# Copyright lowRISC contributors (OpenTitan project).
# Licensed under the Apache License, Version 2.0, see LICENSE for details.
# SPDX-License-Identifier: Apache-2.0
#
# This file was derived by lowRISC contributors (OpenTitan project) from the
# IHP Open PDK SRAM abstract RM_IHPSG13_1P_8192x32_c4.lef
# (https://github.com/IHP-GmbH/IHP-Open-PDK, ihp-sg13g2/libs.ref/sg13g2_sram/lef).
# It is a synthetic abstract, not an IHP release: the macro size and pins come
# from the Liberty view, the pin shapes, power straps and antenna values from
# the IHP abstract. IHP's original notice follows:
#
#   Copyright 2023 IHP PDK Authors
#
#   Licensed under the Apache License, Version 2.0 (the "License");
#   you may not use this file except in compliance with the License.
#   You may obtain a copy of the License at
#
#      https://www.apache.org/licenses/LICENSE-2.0
#
#   Unless required by applicable law or agreed to in writing, software
#   distributed under the License is distributed on an "AS IS" BASIS,
#   WITHOUT WARRANTIES OR CONDITIONS OF ANY KIND, either express or implied.
#   See the License for the specific language governing permissions and
#   limitations under the License.
#
#   Generated on Mon Apr  7 14:15:46 2025
#
# Generated by gen_synthetic_lef.py from the Liberty view. Do not edit.
# Synthetic abstract: no physical layout exists behind this macro.

VERSION 5.7 ;
BUSBITCHARS "[]" ;
DIVIDERCHAR "/" ;

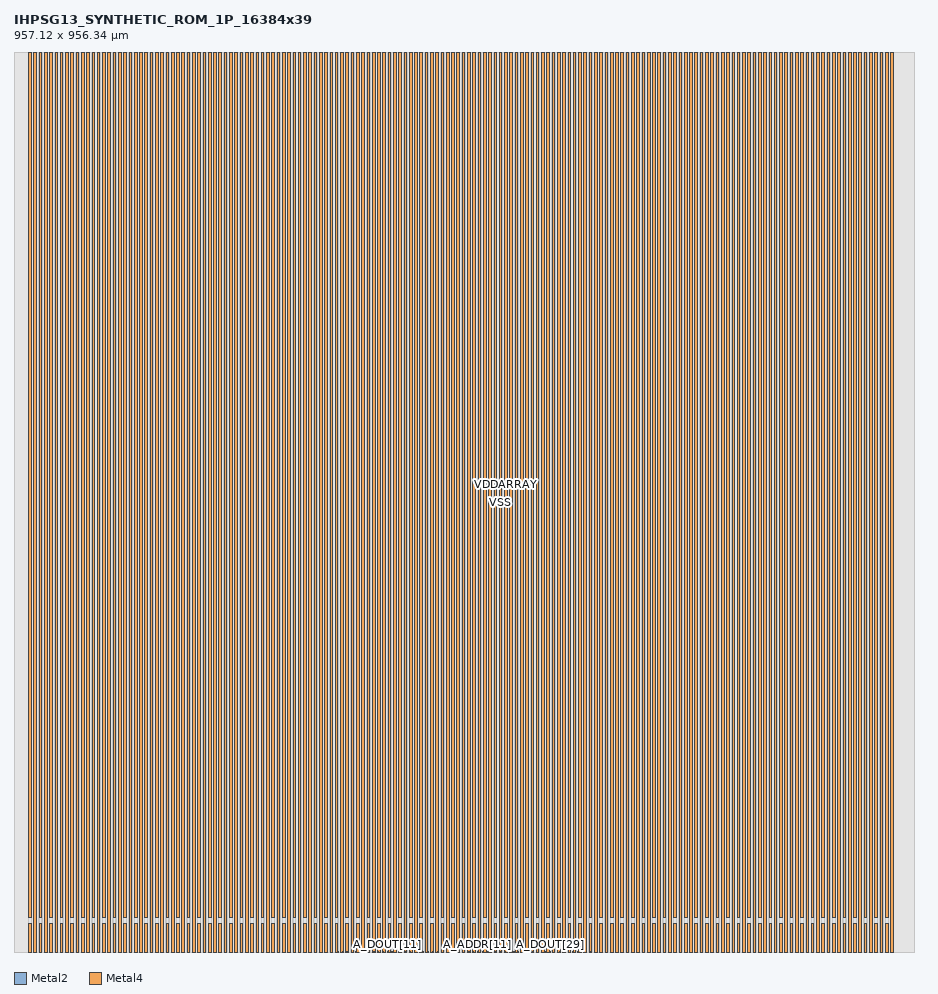
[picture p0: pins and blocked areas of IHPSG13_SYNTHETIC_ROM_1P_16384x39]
MACRO IHPSG13_SYNTHETIC_ROM_1P_16384x39
  CLASS BLOCK ;
  ORIGIN 0 0 ;
  FOREIGN IHPSG13_SYNTHETIC_ROM_1P_16384x39 0 0 ;
  SIZE 957.12 BY 956.34 ;
  SYMMETRY X Y R90 ;
  PIN A_DOUT[0]
    DIRECTION OUTPUT ;
    USE SIGNAL ;
    ANTENNADIFFAREA 0.988 LAYER Metal2 ;
    PORT
      LAYER Metal2 ;
        RECT 344.03 0 344.29 0.26 ;
    END
  END A_DOUT[0]
  PIN A_DOUT[1]
    DIRECTION OUTPUT ;
    USE SIGNAL ;
    ANTENNADIFFAREA 0.988 LAYER Metal2 ;
    PORT
      LAYER Metal2 ;
        RECT 348.83 0 349.09 0.26 ;
    END
  END A_DOUT[1]
  PIN A_DOUT[2]
    DIRECTION OUTPUT ;
    USE SIGNAL ;
    ANTENNADIFFAREA 0.988 LAYER Metal2 ;
    PORT
      LAYER Metal2 ;
        RECT 353.63 0 353.89 0.26 ;
    END
  END A_DOUT[2]
  PIN A_DOUT[3]
    DIRECTION OUTPUT ;
    USE SIGNAL ;
    ANTENNADIFFAREA 0.988 LAYER Metal2 ;
    PORT
      LAYER Metal2 ;
        RECT 358.43 0 358.69 0.26 ;
    END
  END A_DOUT[3]
  PIN A_DOUT[4]
    DIRECTION OUTPUT ;
    USE SIGNAL ;
    ANTENNADIFFAREA 0.988 LAYER Metal2 ;
    PORT
      LAYER Metal2 ;
        RECT 363.23 0 363.49 0.26 ;
    END
  END A_DOUT[4]
  PIN A_DOUT[5]
    DIRECTION OUTPUT ;
    USE SIGNAL ;
    ANTENNADIFFAREA 0.988 LAYER Metal2 ;
    PORT
      LAYER Metal2 ;
        RECT 368.03 0 368.29 0.26 ;
    END
  END A_DOUT[5]
  PIN A_DOUT[6]
    DIRECTION OUTPUT ;
    USE SIGNAL ;
    ANTENNADIFFAREA 0.988 LAYER Metal2 ;
    PORT
      LAYER Metal2 ;
        RECT 372.83 0 373.09 0.26 ;
    END
  END A_DOUT[6]
  PIN A_DOUT[7]
    DIRECTION OUTPUT ;
    USE SIGNAL ;
    ANTENNADIFFAREA 0.988 LAYER Metal2 ;
    PORT
      LAYER Metal2 ;
        RECT 377.63 0 377.89 0.26 ;
    END
  END A_DOUT[7]
  PIN A_DOUT[8]
    DIRECTION OUTPUT ;
    USE SIGNAL ;
    ANTENNADIFFAREA 0.988 LAYER Metal2 ;
    PORT
      LAYER Metal2 ;
        RECT 382.43 0 382.69 0.26 ;
    END
  END A_DOUT[8]
  PIN A_DOUT[9]
    DIRECTION OUTPUT ;
    USE SIGNAL ;
    ANTENNADIFFAREA 0.988 LAYER Metal2 ;
    PORT
      LAYER Metal2 ;
        RECT 387.23 0 387.49 0.26 ;
    END
  END A_DOUT[9]
  PIN A_DOUT[10]
    DIRECTION OUTPUT ;
    USE SIGNAL ;
    ANTENNADIFFAREA 0.988 LAYER Metal2 ;
    PORT
      LAYER Metal2 ;
        RECT 392.03 0 392.29 0.26 ;
    END
  END A_DOUT[10]
  PIN A_DOUT[11]
    DIRECTION OUTPUT ;
    USE SIGNAL ;
    ANTENNADIFFAREA 0.988 LAYER Metal2 ;
    PORT
      LAYER Metal2 ;
        RECT 396.83 0 397.09 0.26 ;
    END
  END A_DOUT[11]
  PIN A_DOUT[12]
    DIRECTION OUTPUT ;
    USE SIGNAL ;
    ANTENNADIFFAREA 0.988 LAYER Metal2 ;
    PORT
      LAYER Metal2 ;
        RECT 401.63 0 401.89 0.26 ;
    END
  END A_DOUT[12]
  PIN A_DOUT[13]
    DIRECTION OUTPUT ;
    USE SIGNAL ;
    ANTENNADIFFAREA 0.988 LAYER Metal2 ;
    PORT
      LAYER Metal2 ;
        RECT 406.43 0 406.69 0.26 ;
    END
  END A_DOUT[13]
  PIN A_DOUT[14]
    DIRECTION OUTPUT ;
    USE SIGNAL ;
    ANTENNADIFFAREA 0.988 LAYER Metal2 ;
    PORT
      LAYER Metal2 ;
        RECT 411.23 0 411.49 0.26 ;
    END
  END A_DOUT[14]
  PIN A_DOUT[15]
    DIRECTION OUTPUT ;
    USE SIGNAL ;
    ANTENNADIFFAREA 0.988 LAYER Metal2 ;
    PORT
      LAYER Metal2 ;
        RECT 416.03 0 416.29 0.26 ;
    END
  END A_DOUT[15]
  PIN A_DOUT[16]
    DIRECTION OUTPUT ;
    USE SIGNAL ;
    ANTENNADIFFAREA 0.988 LAYER Metal2 ;
    PORT
      LAYER Metal2 ;
        RECT 420.83 0 421.09 0.26 ;
    END
  END A_DOUT[16]
  PIN A_DOUT[17]
    DIRECTION OUTPUT ;
    USE SIGNAL ;
    ANTENNADIFFAREA 0.988 LAYER Metal2 ;
    PORT
      LAYER Metal2 ;
        RECT 425.63 0 425.89 0.26 ;
    END
  END A_DOUT[17]
  PIN A_DOUT[18]
    DIRECTION OUTPUT ;
    USE SIGNAL ;
    ANTENNADIFFAREA 0.988 LAYER Metal2 ;
    PORT
      LAYER Metal2 ;
        RECT 430.43 0 430.69 0.26 ;
    END
  END A_DOUT[18]
  PIN A_DLY
    DIRECTION INPUT ;
    USE SIGNAL ;
    ANTENNAMODEL OXIDE1 ;
      ANTENNAGATEAREA 0.20085 LAYER Metal2 ;
    PORT
      LAYER Metal2 ;
        RECT 435.23 0 435.49 0.26 ;
    END
  END A_DLY
  PIN A_ADDR[0]
    DIRECTION INPUT ;
    USE SIGNAL ;
    ANTENNAMODEL OXIDE1 ;
      ANTENNAGATEAREA 0.20085 LAYER Metal2 ;
    PORT
      LAYER Metal2 ;
        RECT 440.03 0 440.29 0.26 ;
    END
  END A_ADDR[0]
  PIN A_ADDR[1]
    DIRECTION INPUT ;
    USE SIGNAL ;
    ANTENNAMODEL OXIDE1 ;
      ANTENNAGATEAREA 0.20085 LAYER Metal2 ;
    PORT
      LAYER Metal2 ;
        RECT 444.83 0 445.09 0.26 ;
    END
  END A_ADDR[1]
  PIN A_ADDR[2]
    DIRECTION INPUT ;
    USE SIGNAL ;
    ANTENNAMODEL OXIDE1 ;
      ANTENNAGATEAREA 0.20085 LAYER Metal2 ;
    PORT
      LAYER Metal2 ;
        RECT 449.63 0 449.89 0.26 ;
    END
  END A_ADDR[2]
  PIN A_ADDR[3]
    DIRECTION INPUT ;
    USE SIGNAL ;
    ANTENNAMODEL OXIDE1 ;
      ANTENNAGATEAREA 0.20085 LAYER Metal2 ;
    PORT
      LAYER Metal2 ;
        RECT 454.43 0 454.69 0.26 ;
    END
  END A_ADDR[3]
  PIN A_ADDR[4]
    DIRECTION INPUT ;
    USE SIGNAL ;
    ANTENNAMODEL OXIDE1 ;
      ANTENNAGATEAREA 0.20085 LAYER Metal2 ;
    PORT
      LAYER Metal2 ;
        RECT 459.23 0 459.49 0.26 ;
    END
  END A_ADDR[4]
  PIN A_ADDR[5]
    DIRECTION INPUT ;
    USE SIGNAL ;
    ANTENNAMODEL OXIDE1 ;
      ANTENNAGATEAREA 0.20085 LAYER Metal2 ;
    PORT
      LAYER Metal2 ;
        RECT 464.03 0 464.29 0.26 ;
    END
  END A_ADDR[5]
  PIN A_ADDR[6]
    DIRECTION INPUT ;
    USE SIGNAL ;
    ANTENNAMODEL OXIDE1 ;
      ANTENNAGATEAREA 0.20085 LAYER Metal2 ;
    PORT
      LAYER Metal2 ;
        RECT 468.83 0 469.09 0.26 ;
    END
  END A_ADDR[6]
  PIN A_ADDR[7]
    DIRECTION INPUT ;
    USE SIGNAL ;
    ANTENNAMODEL OXIDE1 ;
      ANTENNAGATEAREA 0.20085 LAYER Metal2 ;
    PORT
      LAYER Metal2 ;
        RECT 473.63 0 473.89 0.26 ;
    END
  END A_ADDR[7]
  PIN A_ADDR[8]
    DIRECTION INPUT ;
    USE SIGNAL ;
    ANTENNAMODEL OXIDE1 ;
      ANTENNAGATEAREA 0.20085 LAYER Metal2 ;
    PORT
      LAYER Metal2 ;
        RECT 478.43 0 478.69 0.26 ;
    END
  END A_ADDR[8]
  PIN A_ADDR[9]
    DIRECTION INPUT ;
    USE SIGNAL ;
    ANTENNAMODEL OXIDE1 ;
      ANTENNAGATEAREA 0.20085 LAYER Metal2 ;
    PORT
      LAYER Metal2 ;
        RECT 483.23 0 483.49 0.26 ;
    END
  END A_ADDR[9]
  PIN A_ADDR[10]
    DIRECTION INPUT ;
    USE SIGNAL ;
    ANTENNAMODEL OXIDE1 ;
      ANTENNAGATEAREA 0.20085 LAYER Metal2 ;
    PORT
      LAYER Metal2 ;
        RECT 488.03 0 488.29 0.26 ;
    END
  END A_ADDR[10]
  PIN A_ADDR[11]
    DIRECTION INPUT ;
    USE SIGNAL ;
    ANTENNAMODEL OXIDE1 ;
      ANTENNAGATEAREA 0.20085 LAYER Metal2 ;
    PORT
      LAYER Metal2 ;
        RECT 492.83 0 493.09 0.26 ;
    END
  END A_ADDR[11]
  PIN A_ADDR[12]
    DIRECTION INPUT ;
    USE SIGNAL ;
    ANTENNAMODEL OXIDE1 ;
      ANTENNAGATEAREA 0.20085 LAYER Metal2 ;
    PORT
      LAYER Metal2 ;
        RECT 497.63 0 497.89 0.26 ;
    END
  END A_ADDR[12]
  PIN A_ADDR[13]
    DIRECTION INPUT ;
    USE SIGNAL ;
    ANTENNAMODEL OXIDE1 ;
      ANTENNAGATEAREA 0.20085 LAYER Metal2 ;
    PORT
      LAYER Metal2 ;
        RECT 502.43 0 502.69 0.26 ;
    END
  END A_ADDR[13]
  PIN A_REN
    DIRECTION INPUT ;
    USE SIGNAL ;
    ANTENNAMODEL OXIDE1 ;
      ANTENNAGATEAREA 0.20085 LAYER Metal2 ;
    PORT
      LAYER Metal2 ;
        RECT 507.23 0 507.49 0.26 ;
    END
  END A_REN
  PIN A_MEN
    DIRECTION INPUT ;
    USE SIGNAL ;
    ANTENNAMODEL OXIDE1 ;
      ANTENNAGATEAREA 0.20085 LAYER Metal2 ;
    PORT
      LAYER Metal2 ;
        RECT 512.03 0 512.29 0.26 ;
    END
  END A_MEN
  PIN A_CLK
    DIRECTION INPUT ;
    USE SIGNAL ;
    ANTENNAMODEL OXIDE1 ;
      ANTENNAGATEAREA 0.20085 LAYER Metal2 ;
    PORT
      LAYER Metal2 ;
        RECT 516.83 0 517.09 0.26 ;
    END
  END A_CLK
  PIN A_DOUT[19]
    DIRECTION OUTPUT ;
    USE SIGNAL ;
    ANTENNADIFFAREA 0.988 LAYER Metal2 ;
    PORT
      LAYER Metal2 ;
        RECT 521.63 0 521.89 0.26 ;
    END
  END A_DOUT[19]
  PIN A_DOUT[20]
    DIRECTION OUTPUT ;
    USE SIGNAL ;
    ANTENNADIFFAREA 0.988 LAYER Metal2 ;
    PORT
      LAYER Metal2 ;
        RECT 526.43 0 526.69 0.26 ;
    END
  END A_DOUT[20]
  PIN A_DOUT[21]
    DIRECTION OUTPUT ;
    USE SIGNAL ;
    ANTENNADIFFAREA 0.988 LAYER Metal2 ;
    PORT
      LAYER Metal2 ;
        RECT 531.23 0 531.49 0.26 ;
    END
  END A_DOUT[21]
  PIN A_DOUT[22]
    DIRECTION OUTPUT ;
    USE SIGNAL ;
    ANTENNADIFFAREA 0.988 LAYER Metal2 ;
    PORT
      LAYER Metal2 ;
        RECT 536.03 0 536.29 0.26 ;
    END
  END A_DOUT[22]
  PIN A_DOUT[23]
    DIRECTION OUTPUT ;
    USE SIGNAL ;
    ANTENNADIFFAREA 0.988 LAYER Metal2 ;
    PORT
      LAYER Metal2 ;
        RECT 540.83 0 541.09 0.26 ;
    END
  END A_DOUT[23]
  PIN A_DOUT[24]
    DIRECTION OUTPUT ;
    USE SIGNAL ;
    ANTENNADIFFAREA 0.988 LAYER Metal2 ;
    PORT
      LAYER Metal2 ;
        RECT 545.63 0 545.89 0.26 ;
    END
  END A_DOUT[24]
  PIN A_DOUT[25]
    DIRECTION OUTPUT ;
    USE SIGNAL ;
    ANTENNADIFFAREA 0.988 LAYER Metal2 ;
    PORT
      LAYER Metal2 ;
        RECT 550.43 0 550.69 0.26 ;
    END
  END A_DOUT[25]
  PIN A_DOUT[26]
    DIRECTION OUTPUT ;
    USE SIGNAL ;
    ANTENNADIFFAREA 0.988 LAYER Metal2 ;
    PORT
      LAYER Metal2 ;
        RECT 555.23 0 555.49 0.26 ;
    END
  END A_DOUT[26]
  PIN A_DOUT[27]
    DIRECTION OUTPUT ;
    USE SIGNAL ;
    ANTENNADIFFAREA 0.988 LAYER Metal2 ;
    PORT
      LAYER Metal2 ;
        RECT 560.03 0 560.29 0.26 ;
    END
  END A_DOUT[27]
  PIN A_DOUT[28]
    DIRECTION OUTPUT ;
    USE SIGNAL ;
    ANTENNADIFFAREA 0.988 LAYER Metal2 ;
    PORT
      LAYER Metal2 ;
        RECT 564.83 0 565.09 0.26 ;
    END
  END A_DOUT[28]
  PIN A_DOUT[29]
    DIRECTION OUTPUT ;
    USE SIGNAL ;
    ANTENNADIFFAREA 0.988 LAYER Metal2 ;
    PORT
      LAYER Metal2 ;
        RECT 569.63 0 569.89 0.26 ;
    END
  END A_DOUT[29]
  PIN A_DOUT[30]
    DIRECTION OUTPUT ;
    USE SIGNAL ;
    ANTENNADIFFAREA 0.988 LAYER Metal2 ;
    PORT
      LAYER Metal2 ;
        RECT 574.43 0 574.69 0.26 ;
    END
  END A_DOUT[30]
  PIN A_DOUT[31]
    DIRECTION OUTPUT ;
    USE SIGNAL ;
    ANTENNADIFFAREA 0.988 LAYER Metal2 ;
    PORT
      LAYER Metal2 ;
        RECT 579.23 0 579.49 0.26 ;
    END
  END A_DOUT[31]
  PIN A_DOUT[32]
    DIRECTION OUTPUT ;
    USE SIGNAL ;
    ANTENNADIFFAREA 0.988 LAYER Metal2 ;
    PORT
      LAYER Metal2 ;
        RECT 584.03 0 584.29 0.26 ;
    END
  END A_DOUT[32]
  PIN A_DOUT[33]
    DIRECTION OUTPUT ;
    USE SIGNAL ;
    ANTENNADIFFAREA 0.988 LAYER Metal2 ;
    PORT
      LAYER Metal2 ;
        RECT 588.83 0 589.09 0.26 ;
    END
  END A_DOUT[33]
  PIN A_DOUT[34]
    DIRECTION OUTPUT ;
    USE SIGNAL ;
    ANTENNADIFFAREA 0.988 LAYER Metal2 ;
    PORT
      LAYER Metal2 ;
        RECT 593.63 0 593.89 0.26 ;
    END
  END A_DOUT[34]
  PIN A_DOUT[35]
    DIRECTION OUTPUT ;
    USE SIGNAL ;
    ANTENNADIFFAREA 0.988 LAYER Metal2 ;
    PORT
      LAYER Metal2 ;
        RECT 598.43 0 598.69 0.26 ;
    END
  END A_DOUT[35]
  PIN A_DOUT[36]
    DIRECTION OUTPUT ;
    USE SIGNAL ;
    ANTENNADIFFAREA 0.988 LAYER Metal2 ;
    PORT
      LAYER Metal2 ;
        RECT 603.23 0 603.49 0.26 ;
    END
  END A_DOUT[36]
  PIN A_DOUT[37]
    DIRECTION OUTPUT ;
    USE SIGNAL ;
    ANTENNADIFFAREA 0.988 LAYER Metal2 ;
    PORT
      LAYER Metal2 ;
        RECT 608.03 0 608.29 0.26 ;
    END
  END A_DOUT[37]
  PIN A_DOUT[38]
    DIRECTION OUTPUT ;
    USE SIGNAL ;
    ANTENNADIFFAREA 0.988 LAYER Metal2 ;
    PORT
      LAYER Metal2 ;
        RECT 612.83 0 613.09 0.26 ;
    END
  END A_DOUT[38]
  PIN VDD
    DIRECTION INOUT ;
    USE POWER ;
    PORT
      LAYER Metal4 ;
        RECT 15.5 0 18.31 30.425 ;
    END
    PORT
      LAYER Metal4 ;
        RECT 26.74 0 29.55 30.425 ;
    END
    PORT
      LAYER Metal4 ;
        RECT 37.98 0 40.79 30.425 ;
    END
    PORT
      LAYER Metal4 ;
        RECT 49.22 0 52.03 30.425 ;
    END
    PORT
      LAYER Metal4 ;
        RECT 60.46 0 63.27 30.425 ;
    END
    PORT
      LAYER Metal4 ;
        RECT 71.7 0 74.51 30.425 ;
    END
    PORT
      LAYER Metal4 ;
        RECT 82.94 0 85.75 30.425 ;
    END
    PORT
      LAYER Metal4 ;
        RECT 94.18 0 96.99 30.425 ;
    END
    PORT
      LAYER Metal4 ;
        RECT 105.42 0 108.23 30.425 ;
    END
    PORT
      LAYER Metal4 ;
        RECT 116.66 0 119.47 30.425 ;
    END
    PORT
      LAYER Metal4 ;
        RECT 127.9 0 130.71 30.425 ;
    END
    PORT
      LAYER Metal4 ;
        RECT 139.14 0 141.95 30.425 ;
    END
    PORT
      LAYER Metal4 ;
        RECT 150.38 0 153.19 30.425 ;
    END
    PORT
      LAYER Metal4 ;
        RECT 161.62 0 164.43 30.425 ;
    END
    PORT
      LAYER Metal4 ;
        RECT 172.86 0 175.67 30.425 ;
    END
    PORT
      LAYER Metal4 ;
        RECT 184.1 0 186.91 30.425 ;
    END
    PORT
      LAYER Metal4 ;
        RECT 195.34 0 198.15 30.425 ;
    END
    PORT
      LAYER Metal4 ;
        RECT 206.58 0 209.39 30.425 ;
    END
    PORT
      LAYER Metal4 ;
        RECT 217.82 0 220.63 30.425 ;
    END
    PORT
      LAYER Metal4 ;
        RECT 229.06 0 231.87 30.425 ;
    END
    PORT
      LAYER Metal4 ;
        RECT 240.3 0 243.11 30.425 ;
    END
    PORT
      LAYER Metal4 ;
        RECT 251.54 0 254.35 30.425 ;
    END
    PORT
      LAYER Metal4 ;
        RECT 262.78 0 265.59 30.425 ;
    END
    PORT
      LAYER Metal4 ;
        RECT 274.02 0 276.83 30.425 ;
    END
    PORT
      LAYER Metal4 ;
        RECT 285.26 0 288.07 30.425 ;
    END
    PORT
      LAYER Metal4 ;
        RECT 296.5 0 299.31 30.425 ;
    END
    PORT
      LAYER Metal4 ;
        RECT 307.74 0 310.55 30.425 ;
    END
    PORT
      LAYER Metal4 ;
        RECT 318.98 0 321.79 30.425 ;
    END
    PORT
      LAYER Metal4 ;
        RECT 330.22 0 333.03 30.425 ;
    END
    PORT
      LAYER Metal4 ;
        RECT 341.46 0 344.27 30.425 ;
    END
    PORT
      LAYER Metal4 ;
        RECT 352.7 0 355.51 30.425 ;
    END
    PORT
      LAYER Metal4 ;
        RECT 363.94 0 366.75 30.425 ;
    END
    PORT
      LAYER Metal4 ;
        RECT 375.18 0 377.99 30.425 ;
    END
    PORT
      LAYER Metal4 ;
        RECT 386.42 0 389.23 30.425 ;
    END
    PORT
      LAYER Metal4 ;
        RECT 397.66 0 400.47 30.425 ;
    END
    PORT
      LAYER Metal4 ;
        RECT 408.9 0 411.71 30.425 ;
    END
    PORT
      LAYER Metal4 ;
        RECT 420.14 0 422.95 30.425 ;
    END
    PORT
      LAYER Metal4 ;
        RECT 431.38 0 434.19 30.425 ;
    END
    PORT
      LAYER Metal4 ;
        RECT 442.62 0 445.43 30.425 ;
    END
    PORT
      LAYER Metal4 ;
        RECT 453.86 0 456.67 30.425 ;
    END
    PORT
      LAYER Metal4 ;
        RECT 465.1 0 467.91 30.425 ;
    END
    PORT
      LAYER Metal4 ;
        RECT 476.34 0 479.15 30.425 ;
    END
    PORT
      LAYER Metal4 ;
        RECT 487.58 0 490.39 30.425 ;
    END
    PORT
      LAYER Metal4 ;
        RECT 498.82 0 501.63 30.425 ;
    END
    PORT
      LAYER Metal4 ;
        RECT 510.06 0 512.87 30.425 ;
    END
    PORT
      LAYER Metal4 ;
        RECT 521.3 0 524.11 30.425 ;
    END
    PORT
      LAYER Metal4 ;
        RECT 532.54 0 535.35 30.425 ;
    END
    PORT
      LAYER Metal4 ;
        RECT 543.78 0 546.59 30.425 ;
    END
    PORT
      LAYER Metal4 ;
        RECT 555.02 0 557.83 30.425 ;
    END
    PORT
      LAYER Metal4 ;
        RECT 566.26 0 569.07 30.425 ;
    END
    PORT
      LAYER Metal4 ;
        RECT 577.5 0 580.31 30.425 ;
    END
    PORT
      LAYER Metal4 ;
        RECT 588.74 0 591.55 30.425 ;
    END
    PORT
      LAYER Metal4 ;
        RECT 599.98 0 602.79 30.425 ;
    END
    PORT
      LAYER Metal4 ;
        RECT 611.22 0 614.03 30.425 ;
    END
    PORT
      LAYER Metal4 ;
        RECT 622.46 0 625.27 30.425 ;
    END
    PORT
      LAYER Metal4 ;
        RECT 633.7 0 636.51 30.425 ;
    END
    PORT
      LAYER Metal4 ;
        RECT 644.94 0 647.75 30.425 ;
    END
    PORT
      LAYER Metal4 ;
        RECT 656.18 0 658.99 30.425 ;
    END
    PORT
      LAYER Metal4 ;
        RECT 667.42 0 670.23 30.425 ;
    END
    PORT
      LAYER Metal4 ;
        RECT 678.66 0 681.47 30.425 ;
    END
    PORT
      LAYER Metal4 ;
        RECT 689.9 0 692.71 30.425 ;
    END
    PORT
      LAYER Metal4 ;
        RECT 701.14 0 703.95 30.425 ;
    END
    PORT
      LAYER Metal4 ;
        RECT 712.38 0 715.19 30.425 ;
    END
    PORT
      LAYER Metal4 ;
        RECT 723.62 0 726.43 30.425 ;
    END
    PORT
      LAYER Metal4 ;
        RECT 734.86 0 737.67 30.425 ;
    END
    PORT
      LAYER Metal4 ;
        RECT 746.1 0 748.91 30.425 ;
    END
    PORT
      LAYER Metal4 ;
        RECT 757.34 0 760.15 30.425 ;
    END
    PORT
      LAYER Metal4 ;
        RECT 768.58 0 771.39 30.425 ;
    END
    PORT
      LAYER Metal4 ;
        RECT 779.82 0 782.63 30.425 ;
    END
    PORT
      LAYER Metal4 ;
        RECT 791.06 0 793.87 30.425 ;
    END
    PORT
      LAYER Metal4 ;
        RECT 802.3 0 805.11 30.425 ;
    END
    PORT
      LAYER Metal4 ;
        RECT 813.54 0 816.35 30.425 ;
    END
    PORT
      LAYER Metal4 ;
        RECT 824.78 0 827.59 30.425 ;
    END
    PORT
      LAYER Metal4 ;
        RECT 836.02 0 838.83 30.425 ;
    END
    PORT
      LAYER Metal4 ;
        RECT 847.26 0 850.07 30.425 ;
    END
    PORT
      LAYER Metal4 ;
        RECT 858.5 0 861.31 30.425 ;
    END
    PORT
      LAYER Metal4 ;
        RECT 869.74 0 872.55 30.425 ;
    END
    PORT
      LAYER Metal4 ;
        RECT 880.98 0 883.79 30.425 ;
    END
    PORT
      LAYER Metal4 ;
        RECT 892.22 0 895.03 30.425 ;
    END
    PORT
      LAYER Metal4 ;
        RECT 903.46 0 906.27 30.425 ;
    END
    PORT
      LAYER Metal4 ;
        RECT 914.7 0 917.51 30.425 ;
    END
    PORT
      LAYER Metal4 ;
        RECT 925.94 0 928.75 30.425 ;
    END
  END VDD
  PIN VDDARRAY
    DIRECTION INOUT ;
    USE POWER ;
    PORT
      LAYER Metal4 ;
        RECT 15.5 37.065 18.31 956.34 ;
    END
    PORT
      LAYER Metal4 ;
        RECT 26.74 37.065 29.55 956.34 ;
    END
    PORT
      LAYER Metal4 ;
        RECT 37.98 37.065 40.79 956.34 ;
    END
    PORT
      LAYER Metal4 ;
        RECT 49.22 37.065 52.03 956.34 ;
    END
    PORT
      LAYER Metal4 ;
        RECT 60.46 37.065 63.27 956.34 ;
    END
    PORT
      LAYER Metal4 ;
        RECT 71.7 37.065 74.51 956.34 ;
    END
    PORT
      LAYER Metal4 ;
        RECT 82.94 37.065 85.75 956.34 ;
    END
    PORT
      LAYER Metal4 ;
        RECT 94.18 37.065 96.99 956.34 ;
    END
    PORT
      LAYER Metal4 ;
        RECT 105.42 37.065 108.23 956.34 ;
    END
    PORT
      LAYER Metal4 ;
        RECT 116.66 37.065 119.47 956.34 ;
    END
    PORT
      LAYER Metal4 ;
        RECT 127.9 37.065 130.71 956.34 ;
    END
    PORT
      LAYER Metal4 ;
        RECT 139.14 37.065 141.95 956.34 ;
    END
    PORT
      LAYER Metal4 ;
        RECT 150.38 37.065 153.19 956.34 ;
    END
    PORT
      LAYER Metal4 ;
        RECT 161.62 37.065 164.43 956.34 ;
    END
    PORT
      LAYER Metal4 ;
        RECT 172.86 37.065 175.67 956.34 ;
    END
    PORT
      LAYER Metal4 ;
        RECT 184.1 37.065 186.91 956.34 ;
    END
    PORT
      LAYER Metal4 ;
        RECT 195.34 37.065 198.15 956.34 ;
    END
    PORT
      LAYER Metal4 ;
        RECT 206.58 37.065 209.39 956.34 ;
    END
    PORT
      LAYER Metal4 ;
        RECT 217.82 37.065 220.63 956.34 ;
    END
    PORT
      LAYER Metal4 ;
        RECT 229.06 37.065 231.87 956.34 ;
    END
    PORT
      LAYER Metal4 ;
        RECT 240.3 37.065 243.11 956.34 ;
    END
    PORT
      LAYER Metal4 ;
        RECT 251.54 37.065 254.35 956.34 ;
    END
    PORT
      LAYER Metal4 ;
        RECT 262.78 37.065 265.59 956.34 ;
    END
    PORT
      LAYER Metal4 ;
        RECT 274.02 37.065 276.83 956.34 ;
    END
    PORT
      LAYER Metal4 ;
        RECT 285.26 37.065 288.07 956.34 ;
    END
    PORT
      LAYER Metal4 ;
        RECT 296.5 37.065 299.31 956.34 ;
    END
    PORT
      LAYER Metal4 ;
        RECT 307.74 37.065 310.55 956.34 ;
    END
    PORT
      LAYER Metal4 ;
        RECT 318.98 37.065 321.79 956.34 ;
    END
    PORT
      LAYER Metal4 ;
        RECT 330.22 37.065 333.03 956.34 ;
    END
    PORT
      LAYER Metal4 ;
        RECT 341.46 37.065 344.27 956.34 ;
    END
    PORT
      LAYER Metal4 ;
        RECT 352.7 37.065 355.51 956.34 ;
    END
    PORT
      LAYER Metal4 ;
        RECT 363.94 37.065 366.75 956.34 ;
    END
    PORT
      LAYER Metal4 ;
        RECT 375.18 37.065 377.99 956.34 ;
    END
    PORT
      LAYER Metal4 ;
        RECT 386.42 37.065 389.23 956.34 ;
    END
    PORT
      LAYER Metal4 ;
        RECT 397.66 37.065 400.47 956.34 ;
    END
    PORT
      LAYER Metal4 ;
        RECT 408.9 37.065 411.71 956.34 ;
    END
    PORT
      LAYER Metal4 ;
        RECT 420.14 37.065 422.95 956.34 ;
    END
    PORT
      LAYER Metal4 ;
        RECT 431.38 37.065 434.19 956.34 ;
    END
    PORT
      LAYER Metal4 ;
        RECT 442.62 37.065 445.43 956.34 ;
    END
    PORT
      LAYER Metal4 ;
        RECT 453.86 37.065 456.67 956.34 ;
    END
    PORT
      LAYER Metal4 ;
        RECT 465.1 37.065 467.91 956.34 ;
    END
    PORT
      LAYER Metal4 ;
        RECT 476.34 37.065 479.15 956.34 ;
    END
    PORT
      LAYER Metal4 ;
        RECT 487.58 37.065 490.39 956.34 ;
    END
    PORT
      LAYER Metal4 ;
        RECT 498.82 37.065 501.63 956.34 ;
    END
    PORT
      LAYER Metal4 ;
        RECT 510.06 37.065 512.87 956.34 ;
    END
    PORT
      LAYER Metal4 ;
        RECT 521.3 37.065 524.11 956.34 ;
    END
    PORT
      LAYER Metal4 ;
        RECT 532.54 37.065 535.35 956.34 ;
    END
    PORT
      LAYER Metal4 ;
        RECT 543.78 37.065 546.59 956.34 ;
    END
    PORT
      LAYER Metal4 ;
        RECT 555.02 37.065 557.83 956.34 ;
    END
    PORT
      LAYER Metal4 ;
        RECT 566.26 37.065 569.07 956.34 ;
    END
    PORT
      LAYER Metal4 ;
        RECT 577.5 37.065 580.31 956.34 ;
    END
    PORT
      LAYER Metal4 ;
        RECT 588.74 37.065 591.55 956.34 ;
    END
    PORT
      LAYER Metal4 ;
        RECT 599.98 37.065 602.79 956.34 ;
    END
    PORT
      LAYER Metal4 ;
        RECT 611.22 37.065 614.03 956.34 ;
    END
    PORT
      LAYER Metal4 ;
        RECT 622.46 37.065 625.27 956.34 ;
    END
    PORT
      LAYER Metal4 ;
        RECT 633.7 37.065 636.51 956.34 ;
    END
    PORT
      LAYER Metal4 ;
        RECT 644.94 37.065 647.75 956.34 ;
    END
    PORT
      LAYER Metal4 ;
        RECT 656.18 37.065 658.99 956.34 ;
    END
    PORT
      LAYER Metal4 ;
        RECT 667.42 37.065 670.23 956.34 ;
    END
    PORT
      LAYER Metal4 ;
        RECT 678.66 37.065 681.47 956.34 ;
    END
    PORT
      LAYER Metal4 ;
        RECT 689.9 37.065 692.71 956.34 ;
    END
    PORT
      LAYER Metal4 ;
        RECT 701.14 37.065 703.95 956.34 ;
    END
    PORT
      LAYER Metal4 ;
        RECT 712.38 37.065 715.19 956.34 ;
    END
    PORT
      LAYER Metal4 ;
        RECT 723.62 37.065 726.43 956.34 ;
    END
    PORT
      LAYER Metal4 ;
        RECT 734.86 37.065 737.67 956.34 ;
    END
    PORT
      LAYER Metal4 ;
        RECT 746.1 37.065 748.91 956.34 ;
    END
    PORT
      LAYER Metal4 ;
        RECT 757.34 37.065 760.15 956.34 ;
    END
    PORT
      LAYER Metal4 ;
        RECT 768.58 37.065 771.39 956.34 ;
    END
    PORT
      LAYER Metal4 ;
        RECT 779.82 37.065 782.63 956.34 ;
    END
    PORT
      LAYER Metal4 ;
        RECT 791.06 37.065 793.87 956.34 ;
    END
    PORT
      LAYER Metal4 ;
        RECT 802.3 37.065 805.11 956.34 ;
    END
    PORT
      LAYER Metal4 ;
        RECT 813.54 37.065 816.35 956.34 ;
    END
    PORT
      LAYER Metal4 ;
        RECT 824.78 37.065 827.59 956.34 ;
    END
    PORT
      LAYER Metal4 ;
        RECT 836.02 37.065 838.83 956.34 ;
    END
    PORT
      LAYER Metal4 ;
        RECT 847.26 37.065 850.07 956.34 ;
    END
    PORT
      LAYER Metal4 ;
        RECT 858.5 37.065 861.31 956.34 ;
    END
    PORT
      LAYER Metal4 ;
        RECT 869.74 37.065 872.55 956.34 ;
    END
    PORT
      LAYER Metal4 ;
        RECT 880.98 37.065 883.79 956.34 ;
    END
    PORT
      LAYER Metal4 ;
        RECT 892.22 37.065 895.03 956.34 ;
    END
    PORT
      LAYER Metal4 ;
        RECT 903.46 37.065 906.27 956.34 ;
    END
    PORT
      LAYER Metal4 ;
        RECT 914.7 37.065 917.51 956.34 ;
    END
    PORT
      LAYER Metal4 ;
        RECT 925.94 37.065 928.75 956.34 ;
    END
  END VDDARRAY
  PIN VSS
    DIRECTION INOUT ;
    USE GROUND ;
    PORT
      LAYER Metal4 ;
        RECT 21.12 0 23.93 956.34 ;
    END
    PORT
      LAYER Metal4 ;
        RECT 32.36 0 35.17 956.34 ;
    END
    PORT
      LAYER Metal4 ;
        RECT 43.6 0 46.41 956.34 ;
    END
    PORT
      LAYER Metal4 ;
        RECT 54.84 0 57.65 956.34 ;
    END
    PORT
      LAYER Metal4 ;
        RECT 66.08 0 68.89 956.34 ;
    END
    PORT
      LAYER Metal4 ;
        RECT 77.32 0 80.13 956.34 ;
    END
    PORT
      LAYER Metal4 ;
        RECT 88.56 0 91.37 956.34 ;
    END
    PORT
      LAYER Metal4 ;
        RECT 99.8 0 102.61 956.34 ;
    END
    PORT
      LAYER Metal4 ;
        RECT 111.04 0 113.85 956.34 ;
    END
    PORT
      LAYER Metal4 ;
        RECT 122.28 0 125.09 956.34 ;
    END
    PORT
      LAYER Metal4 ;
        RECT 133.52 0 136.33 956.34 ;
    END
    PORT
      LAYER Metal4 ;
        RECT 144.76 0 147.57 956.34 ;
    END
    PORT
      LAYER Metal4 ;
        RECT 156 0 158.81 956.34 ;
    END
    PORT
      LAYER Metal4 ;
        RECT 167.24 0 170.05 956.34 ;
    END
    PORT
      LAYER Metal4 ;
        RECT 178.48 0 181.29 956.34 ;
    END
    PORT
      LAYER Metal4 ;
        RECT 189.72 0 192.53 956.34 ;
    END
    PORT
      LAYER Metal4 ;
        RECT 200.96 0 203.77 956.34 ;
    END
    PORT
      LAYER Metal4 ;
        RECT 212.2 0 215.01 956.34 ;
    END
    PORT
      LAYER Metal4 ;
        RECT 223.44 0 226.25 956.34 ;
    END
    PORT
      LAYER Metal4 ;
        RECT 234.68 0 237.49 956.34 ;
    END
    PORT
      LAYER Metal4 ;
        RECT 245.92 0 248.73 956.34 ;
    END
    PORT
      LAYER Metal4 ;
        RECT 257.16 0 259.97 956.34 ;
    END
    PORT
      LAYER Metal4 ;
        RECT 268.4 0 271.21 956.34 ;
    END
    PORT
      LAYER Metal4 ;
        RECT 279.64 0 282.45 956.34 ;
    END
    PORT
      LAYER Metal4 ;
        RECT 290.88 0 293.69 956.34 ;
    END
    PORT
      LAYER Metal4 ;
        RECT 302.12 0 304.93 956.34 ;
    END
    PORT
      LAYER Metal4 ;
        RECT 313.36 0 316.17 956.34 ;
    END
    PORT
      LAYER Metal4 ;
        RECT 324.6 0 327.41 956.34 ;
    END
    PORT
      LAYER Metal4 ;
        RECT 335.84 0 338.65 956.34 ;
    END
    PORT
      LAYER Metal4 ;
        RECT 347.08 0 349.89 956.34 ;
    END
    PORT
      LAYER Metal4 ;
        RECT 358.32 0 361.13 956.34 ;
    END
    PORT
      LAYER Metal4 ;
        RECT 369.56 0 372.37 956.34 ;
    END
    PORT
      LAYER Metal4 ;
        RECT 380.8 0 383.61 956.34 ;
    END
    PORT
      LAYER Metal4 ;
        RECT 392.04 0 394.85 956.34 ;
    END
    PORT
      LAYER Metal4 ;
        RECT 403.28 0 406.09 956.34 ;
    END
    PORT
      LAYER Metal4 ;
        RECT 414.52 0 417.33 956.34 ;
    END
    PORT
      LAYER Metal4 ;
        RECT 425.76 0 428.57 956.34 ;
    END
    PORT
      LAYER Metal4 ;
        RECT 437 0 439.81 956.34 ;
    END
    PORT
      LAYER Metal4 ;
        RECT 448.24 0 451.05 956.34 ;
    END
    PORT
      LAYER Metal4 ;
        RECT 459.48 0 462.29 956.34 ;
    END
    PORT
      LAYER Metal4 ;
        RECT 470.72 0 473.53 956.34 ;
    END
    PORT
      LAYER Metal4 ;
        RECT 481.96 0 484.77 956.34 ;
    END
    PORT
      LAYER Metal4 ;
        RECT 493.2 0 496.01 956.34 ;
    END
    PORT
      LAYER Metal4 ;
        RECT 504.44 0 507.25 956.34 ;
    END
    PORT
      LAYER Metal4 ;
        RECT 515.68 0 518.49 956.34 ;
    END
    PORT
      LAYER Metal4 ;
        RECT 526.92 0 529.73 956.34 ;
    END
    PORT
      LAYER Metal4 ;
        RECT 538.16 0 540.97 956.34 ;
    END
    PORT
      LAYER Metal4 ;
        RECT 549.4 0 552.21 956.34 ;
    END
    PORT
      LAYER Metal4 ;
        RECT 560.64 0 563.45 956.34 ;
    END
    PORT
      LAYER Metal4 ;
        RECT 571.88 0 574.69 956.34 ;
    END
    PORT
      LAYER Metal4 ;
        RECT 583.12 0 585.93 956.34 ;
    END
    PORT
      LAYER Metal4 ;
        RECT 594.36 0 597.17 956.34 ;
    END
    PORT
      LAYER Metal4 ;
        RECT 605.6 0 608.41 956.34 ;
    END
    PORT
      LAYER Metal4 ;
        RECT 616.84 0 619.65 956.34 ;
    END
    PORT
      LAYER Metal4 ;
        RECT 628.08 0 630.89 956.34 ;
    END
    PORT
      LAYER Metal4 ;
        RECT 639.32 0 642.13 956.34 ;
    END
    PORT
      LAYER Metal4 ;
        RECT 650.56 0 653.37 956.34 ;
    END
    PORT
      LAYER Metal4 ;
        RECT 661.8 0 664.61 956.34 ;
    END
    PORT
      LAYER Metal4 ;
        RECT 673.04 0 675.85 956.34 ;
    END
    PORT
      LAYER Metal4 ;
        RECT 684.28 0 687.09 956.34 ;
    END
    PORT
      LAYER Metal4 ;
        RECT 695.52 0 698.33 956.34 ;
    END
    PORT
      LAYER Metal4 ;
        RECT 706.76 0 709.57 956.34 ;
    END
    PORT
      LAYER Metal4 ;
        RECT 718 0 720.81 956.34 ;
    END
    PORT
      LAYER Metal4 ;
        RECT 729.24 0 732.05 956.34 ;
    END
    PORT
      LAYER Metal4 ;
        RECT 740.48 0 743.29 956.34 ;
    END
    PORT
      LAYER Metal4 ;
        RECT 751.72 0 754.53 956.34 ;
    END
    PORT
      LAYER Metal4 ;
        RECT 762.96 0 765.77 956.34 ;
    END
    PORT
      LAYER Metal4 ;
        RECT 774.2 0 777.01 956.34 ;
    END
    PORT
      LAYER Metal4 ;
        RECT 785.44 0 788.25 956.34 ;
    END
    PORT
      LAYER Metal4 ;
        RECT 796.68 0 799.49 956.34 ;
    END
    PORT
      LAYER Metal4 ;
        RECT 807.92 0 810.73 956.34 ;
    END
    PORT
      LAYER Metal4 ;
        RECT 819.16 0 821.97 956.34 ;
    END
    PORT
      LAYER Metal4 ;
        RECT 830.4 0 833.21 956.34 ;
    END
    PORT
      LAYER Metal4 ;
        RECT 841.64 0 844.45 956.34 ;
    END
    PORT
      LAYER Metal4 ;
        RECT 852.88 0 855.69 956.34 ;
    END
    PORT
      LAYER Metal4 ;
        RECT 864.12 0 866.93 956.34 ;
    END
    PORT
      LAYER Metal4 ;
        RECT 875.36 0 878.17 956.34 ;
    END
    PORT
      LAYER Metal4 ;
        RECT 886.6 0 889.41 956.34 ;
    END
    PORT
      LAYER Metal4 ;
        RECT 897.84 0 900.65 956.34 ;
    END
    PORT
      LAYER Metal4 ;
        RECT 909.08 0 911.89 956.34 ;
    END
    PORT
      LAYER Metal4 ;
        RECT 920.32 0 923.13 956.34 ;
    END
    PORT
      LAYER Metal4 ;
        RECT 931.56 0 934.37 956.34 ;
    END
  END VSS
  OBS
    LAYER Metal1 ;
      RECT 0 0 957.12 956.34 ;
    LAYER Metal2 ;
      RECT 0 1 957.12 956.34 ;
    LAYER Metal3 ;
      RECT 0 1 957.12 956.34 ;
    LAYER Metal4 ;
      RECT 0 0 15.2 956.34 ;
      RECT 18.61 0 20.82 956.34 ;
      RECT 24.23 0 26.44 956.34 ;
      RECT 29.85 0 32.06 956.34 ;
      RECT 35.47 0 37.68 956.34 ;
      RECT 41.09 0 43.3 956.34 ;
      RECT 46.71 0 48.92 956.34 ;
      RECT 52.33 0 54.54 956.34 ;
      RECT 57.95 0 60.16 956.34 ;
      RECT 63.57 0 65.78 956.34 ;
      RECT 69.19 0 71.4 956.34 ;
      RECT 74.81 0 77.02 956.34 ;
      RECT 80.43 0 82.64 956.34 ;
      RECT 86.05 0 88.26 956.34 ;
      RECT 91.67 0 93.88 956.34 ;
      RECT 97.29 0 99.5 956.34 ;
      RECT 102.91 0 105.12 956.34 ;
      RECT 108.53 0 110.74 956.34 ;
      RECT 114.15 0 116.36 956.34 ;
      RECT 119.77 0 121.98 956.34 ;
      RECT 125.39 0 127.6 956.34 ;
      RECT 131.01 0 133.22 956.34 ;
      RECT 136.63 0 138.84 956.34 ;
      RECT 142.25 0 144.46 956.34 ;
      RECT 147.87 0 150.08 956.34 ;
      RECT 153.49 0 155.7 956.34 ;
      RECT 159.11 0 161.32 956.34 ;
      RECT 164.73 0 166.94 956.34 ;
      RECT 170.35 0 172.56 956.34 ;
      RECT 175.97 0 178.18 956.34 ;
      RECT 181.59 0 183.8 956.34 ;
      RECT 187.21 0 189.42 956.34 ;
      RECT 192.83 0 195.04 956.34 ;
      RECT 198.45 0 200.66 956.34 ;
      RECT 204.07 0 206.28 956.34 ;
      RECT 209.69 0 211.9 956.34 ;
      RECT 215.31 0 217.52 956.34 ;
      RECT 220.93 0 223.14 956.34 ;
      RECT 226.55 0 228.76 956.34 ;
      RECT 232.17 0 234.38 956.34 ;
      RECT 237.79 0 240 956.34 ;
      RECT 243.41 0 245.62 956.34 ;
      RECT 249.03 0 251.24 956.34 ;
      RECT 254.65 0 256.86 956.34 ;
      RECT 260.27 0 262.48 956.34 ;
      RECT 265.89 0 268.1 956.34 ;
      RECT 271.51 0 273.72 956.34 ;
      RECT 277.13 0 279.34 956.34 ;
      RECT 282.75 0 284.96 956.34 ;
      RECT 288.37 0 290.58 956.34 ;
      RECT 293.99 0 296.2 956.34 ;
      RECT 299.61 0 301.82 956.34 ;
      RECT 305.23 0 307.44 956.34 ;
      RECT 310.85 0 313.06 956.34 ;
      RECT 316.47 0 318.68 956.34 ;
      RECT 322.09 0 324.3 956.34 ;
      RECT 327.71 0 329.92 956.34 ;
      RECT 333.33 0 335.54 956.34 ;
      RECT 338.95 0 341.16 956.34 ;
      RECT 344.57 0 346.78 956.34 ;
      RECT 350.19 0 352.4 956.34 ;
      RECT 355.81 0 358.02 956.34 ;
      RECT 361.43 0 363.64 956.34 ;
      RECT 367.05 0 369.26 956.34 ;
      RECT 372.67 0 374.88 956.34 ;
      RECT 378.29 0 380.5 956.34 ;
      RECT 383.91 0 386.12 956.34 ;
      RECT 389.53 0 391.74 956.34 ;
      RECT 395.15 0 397.36 956.34 ;
      RECT 400.77 0 402.98 956.34 ;
      RECT 406.39 0 408.6 956.34 ;
      RECT 412.01 0 414.22 956.34 ;
      RECT 417.63 0 419.84 956.34 ;
      RECT 423.25 0 425.46 956.34 ;
      RECT 428.87 0 431.08 956.34 ;
      RECT 434.49 0 436.7 956.34 ;
      RECT 440.11 0 442.32 956.34 ;
      RECT 445.73 0 447.94 956.34 ;
      RECT 451.35 0 453.56 956.34 ;
      RECT 456.97 0 459.18 956.34 ;
      RECT 462.59 0 464.8 956.34 ;
      RECT 468.21 0 470.42 956.34 ;
      RECT 473.83 0 476.04 956.34 ;
      RECT 479.45 0 481.66 956.34 ;
      RECT 485.07 0 487.28 956.34 ;
      RECT 490.69 0 492.9 956.34 ;
      RECT 496.31 0 498.52 956.34 ;
      RECT 501.93 0 504.14 956.34 ;
      RECT 507.55 0 509.76 956.34 ;
      RECT 513.17 0 515.38 956.34 ;
      RECT 518.79 0 521 956.34 ;
      RECT 524.41 0 526.62 956.34 ;
      RECT 530.03 0 532.24 956.34 ;
      RECT 535.65 0 537.86 956.34 ;
      RECT 541.27 0 543.48 956.34 ;
      RECT 546.89 0 549.1 956.34 ;
      RECT 552.51 0 554.72 956.34 ;
      RECT 558.13 0 560.34 956.34 ;
      RECT 563.75 0 565.96 956.34 ;
      RECT 569.37 0 571.58 956.34 ;
      RECT 574.99 0 577.2 956.34 ;
      RECT 580.61 0 582.82 956.34 ;
      RECT 586.23 0 588.44 956.34 ;
      RECT 591.85 0 594.06 956.34 ;
      RECT 597.47 0 599.68 956.34 ;
      RECT 603.09 0 605.3 956.34 ;
      RECT 608.71 0 610.92 956.34 ;
      RECT 614.33 0 616.54 956.34 ;
      RECT 619.95 0 622.16 956.34 ;
      RECT 625.57 0 627.78 956.34 ;
      RECT 631.19 0 633.4 956.34 ;
      RECT 636.81 0 639.02 956.34 ;
      RECT 642.43 0 644.64 956.34 ;
      RECT 648.05 0 650.26 956.34 ;
      RECT 653.67 0 655.88 956.34 ;
      RECT 659.29 0 661.5 956.34 ;
      RECT 664.91 0 667.12 956.34 ;
      RECT 670.53 0 672.74 956.34 ;
      RECT 676.15 0 678.36 956.34 ;
      RECT 681.77 0 683.98 956.34 ;
      RECT 687.39 0 689.6 956.34 ;
      RECT 693.01 0 695.22 956.34 ;
      RECT 698.63 0 700.84 956.34 ;
      RECT 704.25 0 706.46 956.34 ;
      RECT 709.87 0 712.08 956.34 ;
      RECT 715.49 0 717.7 956.34 ;
      RECT 721.11 0 723.32 956.34 ;
      RECT 726.73 0 728.94 956.34 ;
      RECT 732.35 0 734.56 956.34 ;
      RECT 737.97 0 740.18 956.34 ;
      RECT 743.59 0 745.8 956.34 ;
      RECT 749.21 0 751.42 956.34 ;
      RECT 754.83 0 757.04 956.34 ;
      RECT 760.45 0 762.66 956.34 ;
      RECT 766.07 0 768.28 956.34 ;
      RECT 771.69 0 773.9 956.34 ;
      RECT 777.31 0 779.52 956.34 ;
      RECT 782.93 0 785.14 956.34 ;
      RECT 788.55 0 790.76 956.34 ;
      RECT 794.17 0 796.38 956.34 ;
      RECT 799.79 0 802 956.34 ;
      RECT 805.41 0 807.62 956.34 ;
      RECT 811.03 0 813.24 956.34 ;
      RECT 816.65 0 818.86 956.34 ;
      RECT 822.27 0 824.48 956.34 ;
      RECT 827.89 0 830.1 956.34 ;
      RECT 833.51 0 835.72 956.34 ;
      RECT 839.13 0 841.34 956.34 ;
      RECT 844.75 0 846.96 956.34 ;
      RECT 850.37 0 852.58 956.34 ;
      RECT 855.99 0 858.2 956.34 ;
      RECT 861.61 0 863.82 956.34 ;
      RECT 867.23 0 869.44 956.34 ;
      RECT 872.85 0 875.06 956.34 ;
      RECT 878.47 0 880.68 956.34 ;
      RECT 884.09 0 886.3 956.34 ;
      RECT 889.71 0 891.92 956.34 ;
      RECT 895.33 0 897.54 956.34 ;
      RECT 900.95 0 903.16 956.34 ;
      RECT 906.57 0 908.78 956.34 ;
      RECT 912.19 0 914.4 956.34 ;
      RECT 917.81 0 920.02 956.34 ;
      RECT 923.43 0 925.64 956.34 ;
      RECT 929.05 0 931.26 956.34 ;
      RECT 934.67 0 957.12 956.34 ;
      RECT 15.5 30.725 18.31 36.765 ;
      RECT 26.74 30.725 29.55 36.765 ;
      RECT 37.98 30.725 40.79 36.765 ;
      RECT 49.22 30.725 52.03 36.765 ;
      RECT 60.46 30.725 63.27 36.765 ;
      RECT 71.7 30.725 74.51 36.765 ;
      RECT 82.94 30.725 85.75 36.765 ;
      RECT 94.18 30.725 96.99 36.765 ;
      RECT 105.42 30.725 108.23 36.765 ;
      RECT 116.66 30.725 119.47 36.765 ;
      RECT 127.9 30.725 130.71 36.765 ;
      RECT 139.14 30.725 141.95 36.765 ;
      RECT 150.38 30.725 153.19 36.765 ;
      RECT 161.62 30.725 164.43 36.765 ;
      RECT 172.86 30.725 175.67 36.765 ;
      RECT 184.1 30.725 186.91 36.765 ;
      RECT 195.34 30.725 198.15 36.765 ;
      RECT 206.58 30.725 209.39 36.765 ;
      RECT 217.82 30.725 220.63 36.765 ;
      RECT 229.06 30.725 231.87 36.765 ;
      RECT 240.3 30.725 243.11 36.765 ;
      RECT 251.54 30.725 254.35 36.765 ;
      RECT 262.78 30.725 265.59 36.765 ;
      RECT 274.02 30.725 276.83 36.765 ;
      RECT 285.26 30.725 288.07 36.765 ;
      RECT 296.5 30.725 299.31 36.765 ;
      RECT 307.74 30.725 310.55 36.765 ;
      RECT 318.98 30.725 321.79 36.765 ;
      RECT 330.22 30.725 333.03 36.765 ;
      RECT 341.46 30.725 344.27 36.765 ;
      RECT 352.7 30.725 355.51 36.765 ;
      RECT 363.94 30.725 366.75 36.765 ;
      RECT 375.18 30.725 377.99 36.765 ;
      RECT 386.42 30.725 389.23 36.765 ;
      RECT 397.66 30.725 400.47 36.765 ;
      RECT 408.9 30.725 411.71 36.765 ;
      RECT 420.14 30.725 422.95 36.765 ;
      RECT 431.38 30.725 434.19 36.765 ;
      RECT 442.62 30.725 445.43 36.765 ;
      RECT 453.86 30.725 456.67 36.765 ;
      RECT 465.1 30.725 467.91 36.765 ;
      RECT 476.34 30.725 479.15 36.765 ;
      RECT 487.58 30.725 490.39 36.765 ;
      RECT 498.82 30.725 501.63 36.765 ;
      RECT 510.06 30.725 512.87 36.765 ;
      RECT 521.3 30.725 524.11 36.765 ;
      RECT 532.54 30.725 535.35 36.765 ;
      RECT 543.78 30.725 546.59 36.765 ;
      RECT 555.02 30.725 557.83 36.765 ;
      RECT 566.26 30.725 569.07 36.765 ;
      RECT 577.5 30.725 580.31 36.765 ;
      RECT 588.74 30.725 591.55 36.765 ;
      RECT 599.98 30.725 602.79 36.765 ;
      RECT 611.22 30.725 614.03 36.765 ;
      RECT 622.46 30.725 625.27 36.765 ;
      RECT 633.7 30.725 636.51 36.765 ;
      RECT 644.94 30.725 647.75 36.765 ;
      RECT 656.18 30.725 658.99 36.765 ;
      RECT 667.42 30.725 670.23 36.765 ;
      RECT 678.66 30.725 681.47 36.765 ;
      RECT 689.9 30.725 692.71 36.765 ;
      RECT 701.14 30.725 703.95 36.765 ;
      RECT 712.38 30.725 715.19 36.765 ;
      RECT 723.62 30.725 726.43 36.765 ;
      RECT 734.86 30.725 737.67 36.765 ;
      RECT 746.1 30.725 748.91 36.765 ;
      RECT 757.34 30.725 760.15 36.765 ;
      RECT 768.58 30.725 771.39 36.765 ;
      RECT 779.82 30.725 782.63 36.765 ;
      RECT 791.06 30.725 793.87 36.765 ;
      RECT 802.3 30.725 805.11 36.765 ;
      RECT 813.54 30.725 816.35 36.765 ;
      RECT 824.78 30.725 827.59 36.765 ;
      RECT 836.02 30.725 838.83 36.765 ;
      RECT 847.26 30.725 850.07 36.765 ;
      RECT 858.5 30.725 861.31 36.765 ;
      RECT 869.74 30.725 872.55 36.765 ;
      RECT 880.98 30.725 883.79 36.765 ;
      RECT 892.22 30.725 895.03 36.765 ;
      RECT 903.46 30.725 906.27 36.765 ;
      RECT 914.7 30.725 917.51 36.765 ;
      RECT 925.94 30.725 928.75 36.765 ;
  END
END IHPSG13_SYNTHETIC_ROM_1P_16384x39

END LIBRARY
